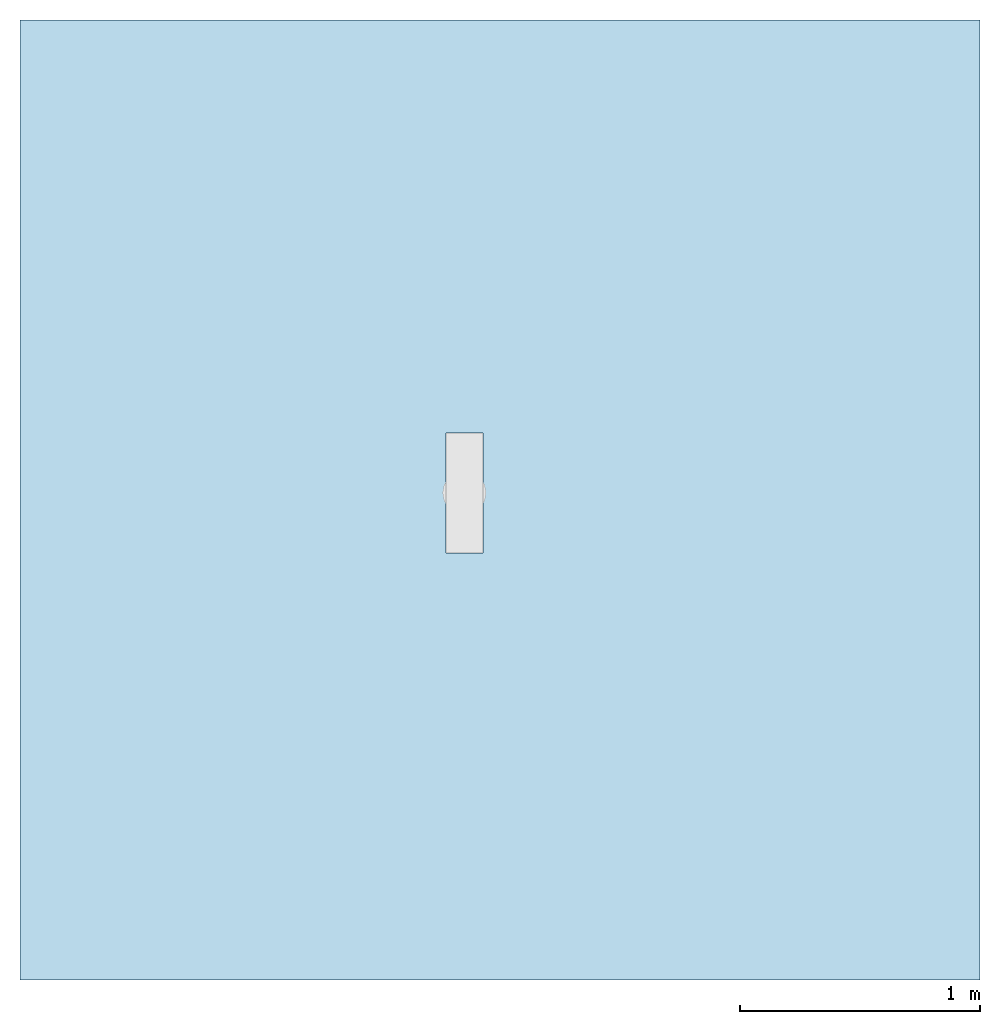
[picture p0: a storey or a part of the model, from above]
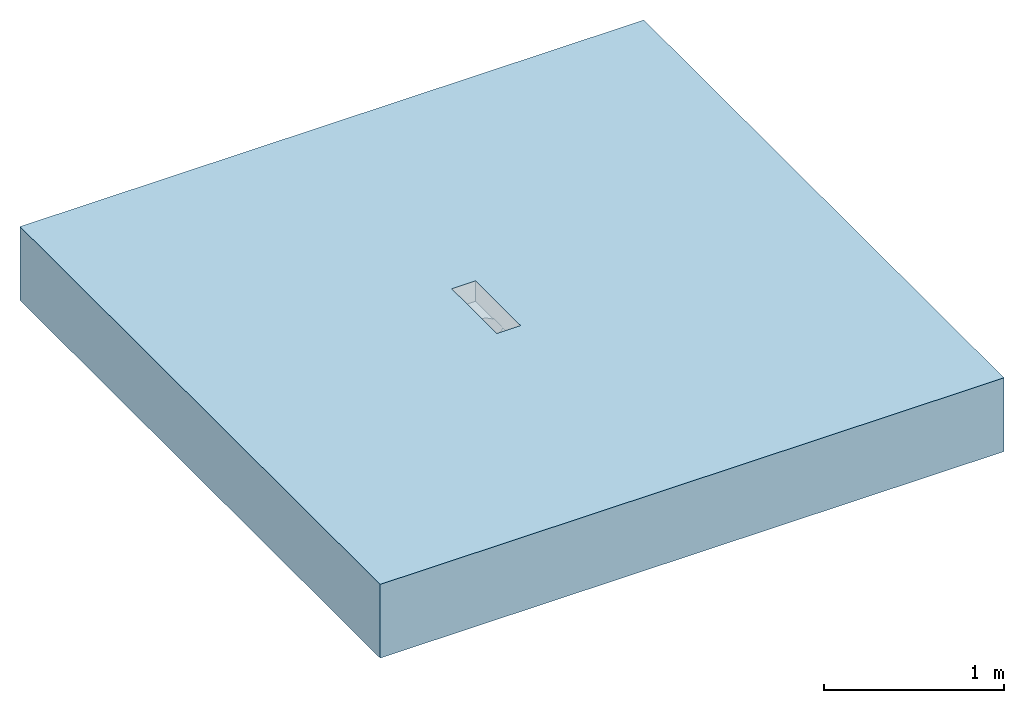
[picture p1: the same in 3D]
Properties of the parts of a building model (IFC2X3)

# File
Description: ViewDefinition [CoordinationView]
File name: 105383 - Discreet Channel Gully Channel - 500mm LG - Invert Depth 125mm.ifc
Time: 2014-03-19T13:43:35
Written by: Autodesk Revit 2013
Made in: 20120221_2030(x64)

# IfcProject, Project Number
LongName: Project Name; Phase: Project Status

# IfcSite, Default
RefLatitude: 42, 21, 30, 344238; RefLongitude: -71, -3, -35, -194702; RefElevation: 0 mm

# IfcBuilding
Pset_BuildingCommon - NumberOfStoreys: 1
Other - Project Address: ## Street City, State Zip; Project Issue Date: Issue Date; Project Name: Project Name; Client Name: Owner; Project Status: Project Status; Project Number: Project Number

# IfcBuildingStorey, Level 1
LongName: Level 1; Elevation: 0 mm
Constraints - Elevation Base: 0; Elevation: 0 mm
Graphics - Symbol at End 2 Default: yes; Line Weight: 1; Color: 0; Symbol: M_Level Head - Circle: M_Level Head - Circle; Symbol at End 1 Default: no; Line Pattern: Center
Identity Data - Name: Level 1; Structural: no; Building Story: yes
Dimensions - Computation Height: 0 mm

# IfcFlowTerminal: 105383 - Discreet Channel Gully Channel - 500mm LG - Invert Depth 125mm, ACO BD Modular 125 Discreet Outlet Units:105383 - Discreet Channel Gully Channel - 500mm LG - Invert Depth 125mm:105383 - Discreet Channel Gully Channel - 500mm LG - Invert Depth 125mm:212888
In: Level 1
Material: Rubber, Nitrile, Stainless Steel AISI 304, Polystyrene, High Impact
Other - Invert Depth Detail: 126.5 mm; Discreet Channel Gully: yes; 408057: 500 mm; 408081: 500 mm; 408083H: 133 mm; 408055H: 133 mm; 408083: 500 mm; PVC Infill (26270): 1000 mm; Rigid PVC Extrusion (49061): 0 mm; 408079H: 133 mm; 408079: 500 mm; 408059H: 133 mm; Flexible PVC Seal (49062): 0 mm; 408081H: 133 mm; 408059: 500 mm; Neoprene Gasket: 1; 408057 H: 133 mm; 408055: 250 mm
Construction - End Plate Invert 2: no; End Plate Invert 1: no; 105844 - Slip Resistant Quadrato Locked - Stainless Steel 304 - 500mm long: no; 21740 - Ladder - Stainless Steel 304 - 500mm long: no; 26270_PVC Infill: yes; 15704 - Composite - Black Composite - 500mm long: no; 21910 - Grating - Slip Resistant Mesh - Stainless Steel 304 - 500mm long: no; 408079_Telescopic_Horizontal Outlet Ø_110mm: no; 105505 - Perforated Locked - Stainless Steel 304 - 500mm long: no; 105539 - Intercept - Stainless Steel 304 - 500mm long: no; 10735 - Composite - White Composite - 500mm long: no; 402072 - Grating - Heal Safe Locked - Stainless Steel 304 - 500mm long: no; 21790 - Plastic - White Plastic - 500mm long: no; 408200 - Outlet Foul Air Trap: no; Min & Max Table for Horizontal Gully Outlet: no; 408059_Telescopic_Vertical Outlet Ø_110mm: no; 105384 - Sediment Basket: no; 105537 - Intercept Locked - Stainless Steel 304 - 500mm long: no; 105846 - Slip Resistant Intercept - Stainless Steel 304 - 500mm long: no; 408083_Telescopic_Horizontal Outlet Ø_110mm: no; 105519 - Slotted Locked - Stainless Steel 304 - 500mm long: no; 408055_Telescopic_Vertical Outlet Ø_110mm: yes; 105848 - Slip Resistant Intercept Locked - Stainless Steel 304 - 500mm long: no; 21920 - Grating - Plain Mesh - Stainless Steel 304 - 500mm long: no; 49061 & 49062_Vinyl Seal: no; 408057_Telescopic_Vertical Outlet Ø_110mm: no; 105842 - Slip Resistant Quadrato - Stainless Steel 304 - 500mm long: no; 21710 - Grating - Slip Resistant Mesh - Stainless Steel 304 - 500mm long: no; 105521 - Slotted Locked - Stainless Steel 304 - 500mm long: no; 105528 - Quadrato Locked - Stainless Steel 304 - 500mm long: no; Min & Max Table for Vertical Gully Outlet: no; 408081_Telescopic_Horizontal Outlet Ø_110mm: no; 21720 - Grating - Plain Mesh - Stainless Steel 304 - 500mm long: no; 96819 - Grating - Heal Safe - Stainless Steel 304 - 500mm long: no; 105530 - Quadrato - Stainless Steel 304 - 500mm long: no; Detail 125mm: yes; Detail 95mm: no; Detail 65mm: no; Grating: yes
Mechanical - System Classification: Sanitary
Phasing - Phase Created: New Construction
Dimensions - Horizontal Void Height: 104.5 mm; Horizontal Gully Void Height Start: -1 mm; Horizontal Gully Void Height End: 1 mm; Vertical Gully Void Height End: -275.5 mm; Top Plate Radius: 91 mm; Vertical Gully Void Height Start: -6.5 mm; Length Channel: -497 mm; Endplate Position: 500 mm; Grating Void Cut Length: 500 mm; Depth: 104 mm; Spigot Distance: 250 mm; End Connection Plate End: -500 mm; Floor Cut Void Height: 137.8 mm; Invert Depth: 125 mm; End Connection Plate Start: -497 mm; Grating Height: 21 mm
Identity Data - Mark: 3; E-mail Sales: abdcommercial@aco.co.uk; Watermarked With: BIM Manager Premium Suite.; Fax: +44 (0)1462 851490; Watermark2: This file is water marked and users are prohibited to reproduce, adapt, distribute this information.; Watermark1: This file is the property of ACO Technologies PLC.; Watermarked By: www.acobd.com; Website: www.acobd.com; Telephone: +44 (0)1462 816666; Manufacturer: ACO Building Drainage; E-mail Technical: abdtechnical@aco.co.uk; Address: ACO Business Centre, Caxton Road, Bedford, MK41 0LF; Cost: 0
Constraints - Level: Level: Level 1
Model Properties - Grating Product Code 21790: Load Class A15 - Plastic - White Plastic - 500mm long - 0.6kg; End Plate Product Code 105103: N/A; Grating Product Code 96819: Load Class B125 - Heal Safe - Stainless Steel 304 - 500mm long - 2.0kg; Grating Product Code 105537: Load Class A15 - Intercept Locked - Stainless Steel 304 - 500mm long - 1.8kg; Grating Product Code 15704: Load Class C250 - Composite - Black Composite - 500mm long - 1.2kg; Product Code 408205: Friction Ring Installation Set - Nitrile - 0.07kg; Grating Product Code 105846: Load Class A15 - Slip Resistant Intercept - Stainless Steel 304 - 500mm long - 1.8kg; Grating Product Code 21740: Load Class C250 - Ladder - Stainless Steel 304 - 500mm long - 2.0kg; End Plate Product Code 105101: N/A; Grating Product Code 105842: Load Class A15 - Slip Resistant Quadrato - Stainless Steel 304 - 500mm long - 1.6kg; Grating Product Code 21920: Load Class C250 - Plain Mesh - Stainless Steel 304 - 500mm long - 2.2kg; Grating Product Code 105848: Load Class A15 - Slip Resistant Intercept Locked - Stainless Steel 304 - 500mm long - 1.8kg; Gully Product Code 408057: Telescopic - 110mm Ø Vertical Outlet - Stainless Steel 304 - Adhesive Bonding Flange - Flow Rate 3.9 to 4.2 l/s - 3.3kg; Grating Product Code 402072: Load Class B125 - Heal Safe Locked - Stainless Steel 304 - 500mm long - 2.0kg; Grating Product Code 105530: Load Class A15 - Quadrato - Stainless Steel 304 - 500mm long - 1.6kg; Gully Product Code 408083: Telescopic - 110mm Ø Horizontal Outlet - Stainless Steel 304 - Mechanical Clamping Flange - Flow Rate 3.2 to 3.9 l/s - 4.1kg; Product Code 408200: 110mm Ø Outlet Foul Air Trap - Stainless Steel 304 - 0.8kg; Gully Product Code 408079: Telescopic - 110mm Ø Horizontal Outlet - Stainless Steel 304 - Location Flange - Flow Rate 3.2 to 3.9 l/s - 2.2kg; Grating Product Code 105539: Load Class A15 - Intercept - Stainless Steel 304 - 500mm long - 1.8kg; Grating Product Code 105528: Load Class A15 - Quadrato Locked - Stainless Steel 304 - 500mm long - 1.6kg; End Plate Product Code 105105: End Plate Stainless Steel 304 for Invert Depth - 125mm - 0.29Kg; Grating Product Code 10735: Load Class C250 - Composite - White Composite - 500mm long - 1.2kg; Grating Product Code 105505: Load Class C250 - Perforated Locked - Stainless Steel 304 - 500mm long - 1.8kg; Product Code 408201: Foul Air Trap Support Ring - Nitrile - 0.1kg; Gully Product Code 408081: Telescopic - 110mm Ø Horizontal Outlet - Stainless Steel 304 - Adhesive Bonding Flange - Flow Rate 3.2 to 3.9 l/s - 3.2kg; Grating Product Code 105521: Load Class C250 - Slotted Locked - Stainless Steel 304 - 500mm long - 2.3kg; Grating Product Code 21710: Load Class A15 - Slip Resistant Mesh - Stainless Steel 304 - 500mm long - 1.6kg; Product Code 105384: Sediment Basket - Stainless Steel 304 - Flow Rate 0.55 l/s - 0.1kg; Grating Product Code 105519: Load Class A15 - Slotted Locked - Stainless Steel 304 - 500mm long - 1.0kg; Grating Product Code 21910: Load Class C250 - Slip Resistant Mesh - Stainless Steel 304 - 500mm long - 2.2kg; Gully Product Code 408055: Telescopic - 110mm Ø Vertical Outlet - Stainless Steel 304 - Location Flange - Flow Rate 3.9 to 4.2 l/s - 2.3kg; Grating Product Code 105844: Load Class A15 - Slip Resistant Quadrato Locked - Stainless Steel 304 - 500mm long - 1.6kg; Gully Product Code 408059: Telescopic - 110mm Ø Vertical Outlet - Stainless Steel 304 - Mechanical Clamping Flange - Flow Rate 3.9 to 4.2 l/s - 4.3kg; Grating Product Code 21720: Load Class A15 - Plain Mesh - Stainless Steel 304 - 500mm long - 1.6kg
General - Load Class: A15 - C250; Channel Colour: Mid Grey; Product Type: Stainless Steel Channel Drainage System; Weight (Kg): 4.0; Product Standard: BS EN 1433:2002, CE marked; Product Range: ACO Modular 125; Product Description: ACO Modular 125 Discreet Channel Gully Unit; Product Code: 105383; Dimensions (LxWxH): 500 x 153 x 125; Installation guidelines: X:\Electronic Literature\ABD Electronic Literature\Standard Stainless Steel and Galvanised Steel Channels\ACO Modular 125\ACO Modular 125.pdf; Channel Recyclable: Fully recyclable; Seal Recycled Material Content: 0%; Channel Material: Stainless Steel Grade 304; Seal Colour: Black; Channel Recycled Material Content: 60-70%; NBS Specification: NBS Section Q10 Kerbs/edgings/channels/paving accessories, Clause 180 Drainage Channel Systems; Seal Material: Neoprene; Price: POA - contact ACO; Maintenance guidelines: X:\Electronic Literature\ABD Electronic Literature\Standard Stainless Steel and Galvanised Steel Channels\ACO Modular 125\ACO Modular 125.pdf; Seal Recyclable: Fully recyclable

# IfcOpeningElement: Recess
In: Level 1
Constraints - Height Offset From Level: 0 mm; Related to Mass: no; Level: Level: Level 1; Room Bounding: yes
Dimensions - Thickness: 500 mm; Volume: 7982576331 mm3; Perimeter: 16000 mm; Area: 16000000 mm2
Phasing - Phase Created: New Construction
Structural - Structural: no; Enable Analytical Model: no
Materials and Finishes - Structural Material: Concrete, Broom Finish
Analytical Properties - Heat Transfer Coefficient (U): 2.092; Roughness: 1; Absorptance: 0.1; Thermal mass: 755550; Thermal Resistance (R): 0.478011
Construction - Function: 0; Default Thickness: 500 mm
Graphics - Coarse Scale Fill Color: 0

# IfcSlab: Floor:Generic Floor - 500mm, Floor:Generic Floor - 500mm:193825
In: Level 1
PredefinedType: FLOOR; Material: Concrete, Broom Finish 500 mm
Constraints - Height Offset From Level: 0 mm; Related to Mass: no; Level: Level: Level 1; Room Bounding: yes
Dimensions - Thickness: 500 mm; Volume: 7982576331 mm3; Perimeter: 16000 mm; Area: 16000000 mm2
Phasing - Phase Created: New Construction
Structural - Structural: no; Enable Analytical Model: no
Pset_SlabCommon - Reference: Generic Floor - 500mm; IsExternal: no; LoadBearing: yes
Materials and Finishes - Structural Material: Concrete, Broom Finish
Analytical Properties - Heat Transfer Coefficient (U): 2.092; Roughness: 1; Absorptance: 0.1; Thermal mass: 755550; Thermal Resistance (R): 0.478011
Construction - Function: 0; Default Thickness: 500 mm
Graphics - Coarse Scale Fill Color: 0
